VERSION 5.7 ;
  NOWIREEXTENSIONATPIN ON ;
  DIVIDERCHAR "/" ;
  BUSBITCHARS "[]" ;
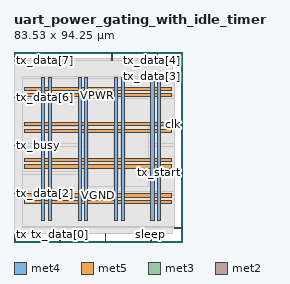
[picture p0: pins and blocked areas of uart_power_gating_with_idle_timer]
MACRO uart_power_gating_with_idle_timer
  CLASS BLOCK ;
  FOREIGN uart_power_gating_with_idle_timer ;
  ORIGIN 0.000 0.000 ;
  SIZE 83.530 BY 94.250 ;
  PIN VGND
    DIRECTION INOUT ;
    USE GROUND ;
    PORT
      LAYER met4 ;
        RECT 17.045 10.640 18.645 81.840 ;
    END
    PORT
      LAYER met4 ;
        RECT 35.100 10.640 36.700 81.840 ;
    END
    PORT
      LAYER met4 ;
        RECT 53.155 10.640 54.755 81.840 ;
    END
    PORT
      LAYER met4 ;
        RECT 71.210 10.640 72.810 81.840 ;
    END
    PORT
      LAYER met5 ;
        RECT 5.280 22.220 77.980 23.820 ;
    END
    PORT
      LAYER met5 ;
        RECT 5.280 39.900 77.980 41.500 ;
    END
    PORT
      LAYER met5 ;
        RECT 5.280 57.580 77.980 59.180 ;
    END
    PORT
      LAYER met5 ;
        RECT 5.280 75.260 77.980 76.860 ;
    END
  END VGND
  PIN VPWR
    DIRECTION INOUT ;
    USE POWER ;
    PORT
      LAYER met4 ;
        RECT 13.745 10.640 15.345 81.840 ;
    END
    PORT
      LAYER met4 ;
        RECT 31.800 10.640 33.400 81.840 ;
    END
    PORT
      LAYER met4 ;
        RECT 49.855 10.640 51.455 81.840 ;
    END
    PORT
      LAYER met4 ;
        RECT 67.910 10.640 69.510 81.840 ;
    END
    PORT
      LAYER met5 ;
        RECT 5.280 18.920 77.980 20.520 ;
    END
    PORT
      LAYER met5 ;
        RECT 5.280 36.600 77.980 38.200 ;
    END
    PORT
      LAYER met5 ;
        RECT 5.280 54.280 77.980 55.880 ;
    END
    PORT
      LAYER met5 ;
        RECT 5.280 71.960 77.980 73.560 ;
    END
  END VPWR
  PIN clk
    DIRECTION INPUT ;
    USE SIGNAL ;
    ANTENNAGATEAREA 0.852000 ;
    PORT
      LAYER met3 ;
        RECT 79.530 57.840 83.530 58.440 ;
    END
  END clk
  PIN rst_n
    DIRECTION INPUT ;
    USE SIGNAL ;
    ANTENNAGATEAREA 0.213000 ;
    PORT
      LAYER met2 ;
        RECT 22.630 90.250 22.910 94.250 ;
    END
  END rst_n
  PIN sleep
    DIRECTION INPUT ;
    USE SIGNAL ;
    ANTENNAGATEAREA 0.196500 ;
    PORT
      LAYER met2 ;
        RECT 67.710 0.000 67.990 4.000 ;
    END
  END sleep
  PIN sleep_ack
    DIRECTION OUTPUT TRISTATE ;
    USE SIGNAL ;
    ANTENNADIFFAREA 0.795200 ;
    PORT
      LAYER met2 ;
        RECT 48.390 90.250 48.670 94.250 ;
    END
  END sleep_ack
  PIN tx
    DIRECTION OUTPUT TRISTATE ;
    USE SIGNAL ;
    ANTENNADIFFAREA 0.795200 ;
    PORT
      LAYER met2 ;
        RECT 0.090 0.000 0.370 4.000 ;
    END
  END tx
  PIN tx_busy
    DIRECTION OUTPUT TRISTATE ;
    USE SIGNAL ;
    ANTENNADIFFAREA 0.795200 ;
    PORT
      LAYER met3 ;
        RECT 0.000 47.640 4.000 48.240 ;
    END
  END tx_busy
  PIN tx_data[0]
    DIRECTION INPUT ;
    USE SIGNAL ;
    ANTENNAGATEAREA 0.196500 ;
    PORT
      LAYER met2 ;
        RECT 22.630 0.000 22.910 4.000 ;
    END
  END tx_data[0]
  PIN tx_data[1]
    DIRECTION INPUT ;
    USE SIGNAL ;
    ANTENNAGATEAREA 0.196500 ;
    PORT
      LAYER met3 ;
        RECT 79.530 6.840 83.530 7.440 ;
    END
  END tx_data[1]
  PIN tx_data[2]
    DIRECTION INPUT ;
    USE SIGNAL ;
    ANTENNAGATEAREA 0.196500 ;
    PORT
      LAYER met3 ;
        RECT 0.000 23.840 4.000 24.440 ;
    END
  END tx_data[2]
  PIN tx_data[3]
    DIRECTION INPUT ;
    USE SIGNAL ;
    ANTENNAGATEAREA 0.196500 ;
    PORT
      LAYER met3 ;
        RECT 79.530 81.640 83.530 82.240 ;
    END
  END tx_data[3]
  PIN tx_data[4]
    DIRECTION INPUT ;
    USE SIGNAL ;
    ANTENNAGATEAREA 0.196500 ;
    PORT
      LAYER met2 ;
        RECT 70.930 90.250 71.210 94.250 ;
    END
  END tx_data[4]
  PIN tx_data[5]
    DIRECTION INPUT ;
    USE SIGNAL ;
    ANTENNAGATEAREA 0.196500 ;
    PORT
      LAYER met2 ;
        RECT 45.170 0.000 45.450 4.000 ;
    END
  END tx_data[5]
  PIN tx_data[6]
    DIRECTION INPUT ;
    USE SIGNAL ;
    ANTENNAGATEAREA 0.196500 ;
    PORT
      LAYER met3 ;
        RECT 0.000 71.440 4.000 72.040 ;
    END
  END tx_data[6]
  PIN tx_data[7]
    DIRECTION INPUT ;
    USE SIGNAL ;
    ANTENNAGATEAREA 0.196500 ;
    PORT
      LAYER met2 ;
        RECT 0.090 90.250 0.370 94.250 ;
    END
  END tx_data[7]
  PIN tx_start
    DIRECTION INPUT ;
    USE SIGNAL ;
    ANTENNAGATEAREA 0.196500 ;
    PORT
      LAYER met3 ;
        RECT 79.530 34.040 83.530 34.640 ;
    END
  END tx_start
  OBS
      LAYER li1 ;
        RECT 5.520 10.795 77.740 81.685 ;
      LAYER met1 ;
        RECT 0.070 10.640 78.590 81.840 ;
      LAYER met2 ;
        RECT 0.650 89.970 22.350 90.850 ;
        RECT 23.190 89.970 48.110 90.850 ;
        RECT 48.950 89.970 70.650 90.850 ;
        RECT 71.490 89.970 78.570 90.850 ;
        RECT 0.100 4.280 78.570 89.970 ;
        RECT 0.650 4.000 22.350 4.280 ;
        RECT 23.190 4.000 44.890 4.280 ;
        RECT 45.730 4.000 67.430 4.280 ;
        RECT 68.270 4.000 78.570 4.280 ;
      LAYER met3 ;
        RECT 4.000 81.240 79.130 82.105 ;
        RECT 4.000 72.440 79.530 81.240 ;
        RECT 4.400 71.040 79.530 72.440 ;
        RECT 4.000 58.840 79.530 71.040 ;
        RECT 4.000 57.440 79.130 58.840 ;
        RECT 4.000 48.640 79.530 57.440 ;
        RECT 4.400 47.240 79.530 48.640 ;
        RECT 4.000 35.040 79.530 47.240 ;
        RECT 4.000 33.640 79.130 35.040 ;
        RECT 4.000 24.840 79.530 33.640 ;
        RECT 4.400 23.440 79.530 24.840 ;
        RECT 4.000 7.840 79.530 23.440 ;
        RECT 4.000 6.975 79.130 7.840 ;
      LAYER met4 ;
        RECT 34.335 27.375 34.700 58.305 ;
        RECT 37.100 27.375 49.455 58.305 ;
        RECT 51.855 27.375 52.755 58.305 ;
        RECT 55.155 27.375 66.865 58.305 ;
  END
END uart_power_gating_with_idle_timer
END LIBRARY

